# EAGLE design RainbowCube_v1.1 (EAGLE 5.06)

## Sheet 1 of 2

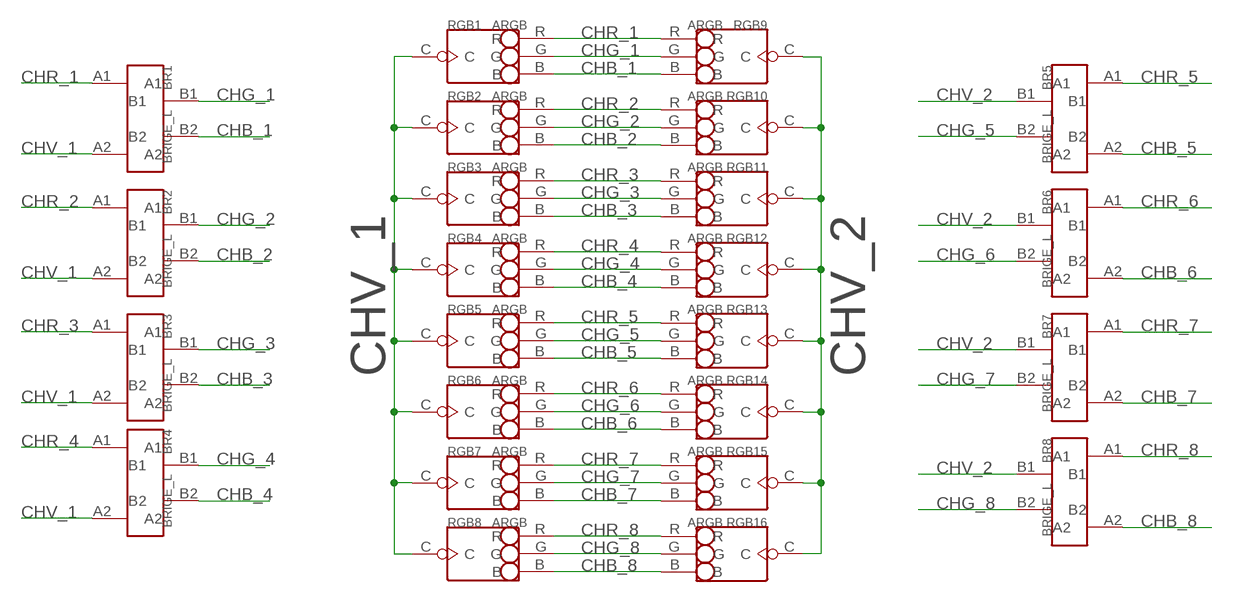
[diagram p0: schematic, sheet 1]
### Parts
BR1  BRIGE_L  [BRIGE_L]
BR2  BRIGE_L  [BRIGE_L]
BR3  BRIGE_L  [BRIGE_L]
BR4  BRIGE_L  [BRIGE_L]
BR5  BRIGE_L  [BRIGE_L]
BR6  BRIGE_L  [BRIGE_L]
BR7  BRIGE_L  [BRIGE_L]
BR8  BRIGE_L  [BRIGE_L]
RGB1  ARGB  [ARGB]
RGB2  ARGB  [ARGB]
RGB3  ARGB  [ARGB]
RGB4  ARGB  [ARGB]
RGB5  ARGB  [ARGB]
RGB6  ARGB  [ARGB]
RGB7  ARGB  [ARGB]
RGB8  ARGB  [ARGB]
RGB9  ARGB  [ARGB]
RGB10  ARGB  [ARGB]
RGB11  ARGB  [ARGB]
RGB12  ARGB  [ARGB]
RGB13  ARGB  [ARGB]
RGB14  ARGB  [ARGB]
RGB15  ARGB  [ARGB]
RGB16  ARGB  [ARGB]

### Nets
CHB_1: BR1.B2 RGB1.B RGB9.B
CHB_2: BR2.B2 RGB2.B RGB10.B
CHB_3: BR3.B2 RGB3.B RGB11.B
CHB_4: BR4.B2 RGB4.B RGB12.B
CHB_5: BR5.A2 RGB5.B RGB13.B
CHB_6: BR6.A2 RGB6.B RGB14.B
CHB_7: BR7.A2 RGB7.B RGB15.B
CHB_8: BR8.A2 RGB8.B RGB16.B
CHG_1: BR1.B1 RGB1.G RGB9.G
CHG_2: BR2.B1 RGB2.G RGB10.G
CHG_3: BR3.B1 RGB3.G RGB11.G
CHG_4: BR4.B1 RGB4.G RGB12.G
CHG_5: BR5.B2 RGB5.G RGB13.G
CHG_6: BR6.B2 RGB6.G RGB14.G
CHG_7: BR7.B2 RGB7.G RGB15.G
CHG_8: BR8.B2 RGB8.G RGB16.G
CHR_1: BR1.A1 RGB1.R RGB9.R
CHR_2: BR2.A1 RGB2.R RGB10.R
CHR_3: BR3.A1 RGB3.R RGB11.R
CHR_4: BR4.A1 RGB4.R RGB12.R
CHR_5: BR5.A1 RGB5.R RGB13.R
CHR_6: BR6.A1 RGB6.R RGB14.R
CHR_7: BR7.A1 RGB7.R RGB15.R
CHR_8: BR8.A1 RGB8.R RGB16.R
CHV_1: BR1.A2 BR2.A2 BR3.A2 BR4.A2 RGB1.C RGB2.C RGB3.C RGB4.C RGB5.C RGB6.C RGB7.C RGB8.C
CHV_2: BR5.B1 BR6.B1 BR7.B1 BR8.B1 RGB9.C RGB10.C RGB11.C RGB12.C RGB13.C RGB14.C RGB15.C RGB16.C

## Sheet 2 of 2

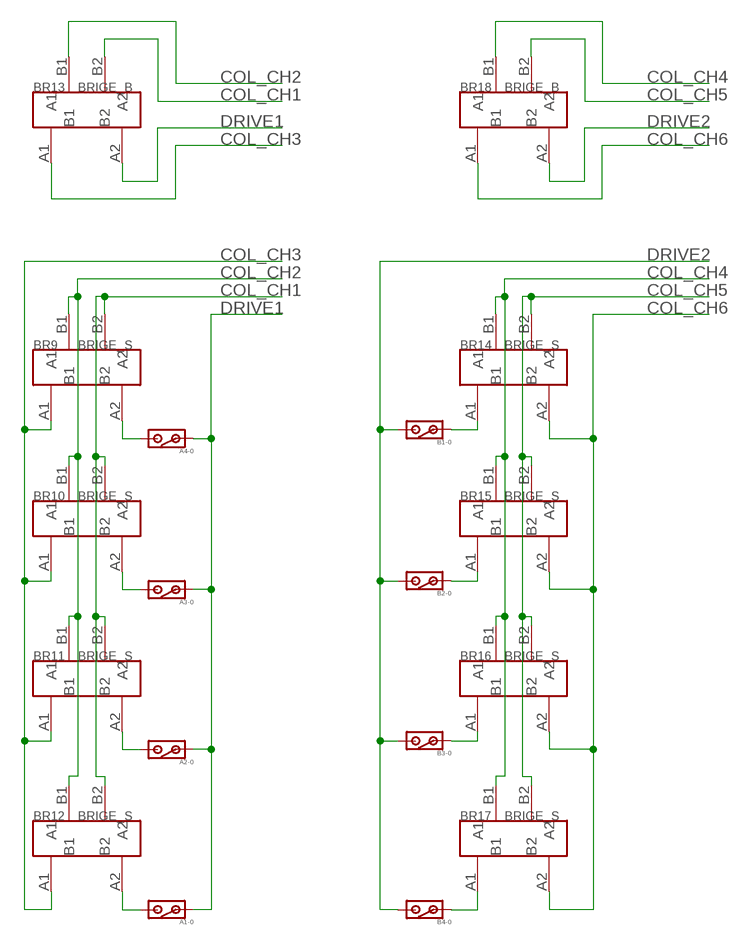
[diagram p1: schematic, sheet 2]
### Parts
A1-0  JP_SW  [JP_SW]
A2-0  JP_SW  [JP_SW]
A3-0  JP_SW  [JP_SW]
A4-0  JP_SW  [JP_SW]
B1-0  JP_SW  [JP_SW]
B2-0  JP_SW  [JP_SW]
B3-0  JP_SW  [JP_SW]
B4-0  JP_SW  [JP_SW]
BR9  BRIGE_S  [BRIGE_S]
BR10  BRIGE_S  [BRIGE_S]
BR11  BRIGE_S  [BRIGE_S]
BR12  BRIGE_S  [BRIGE_S]
BR13  BRIGE_B  [BRIGE_B]
BR14  BRIGE_S  [BRIGE_S]
BR15  BRIGE_S  [BRIGE_S]
BR16  BRIGE_S  [BRIGE_S]
BR17  BRIGE_S  [BRIGE_S]
BR18  BRIGE_B  [BRIGE_B]

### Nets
COL_CH1: BR9.B2 BR10.B2 BR11.B2 BR12.B2 BR13.B2
COL_CH2: BR9.B1 BR10.B1 BR11.B1 BR12.B1 BR13.B1
COL_CH3: BR9.A1 BR10.A1 BR11.A1 BR12.A1 BR13.A1
COL_CH4: BR14.B1 BR15.B1 BR16.B1 BR17.B1 BR18.B1
COL_CH5: BR14.B2 BR15.B2 BR16.B2 BR17.B2 BR18.B2
COL_CH6: BR14.A2 BR15.A2 BR16.A2 BR17.A2 BR18.A1
DRIVE1: A1-0.1 A2-0.1 A3-0.1 A4-0.1 BR13.A2
DRIVE2: B1-0.2 B2-0.2 B3-0.2 B4-0.2 BR18.A2
N$1: B4-0.1 BR17.A1
N$6: B1-0.1 BR14.A1
N$7: B2-0.1 BR15.A1
N$13: B3-0.1 BR16.A1
N$47: A4-0.2 BR9.A2
N$48: A3-0.2 BR10.A2
N$49: A2-0.2 BR11.A2
N$50: A1-0.2 BR12.A2

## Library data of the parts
A1-0 A2-0 A3-0 A4-0 B1-0 B2-0 B3-0 B4-0 = CPT_SMD:JP_SW
BR1-BR18 = CONNECTER:BRIGE
RGB1-RGB16 = CPT_CJ:ARGB

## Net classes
0 default: width 0.003 mm, drill 0.254 mm, clearance 0.152 mm

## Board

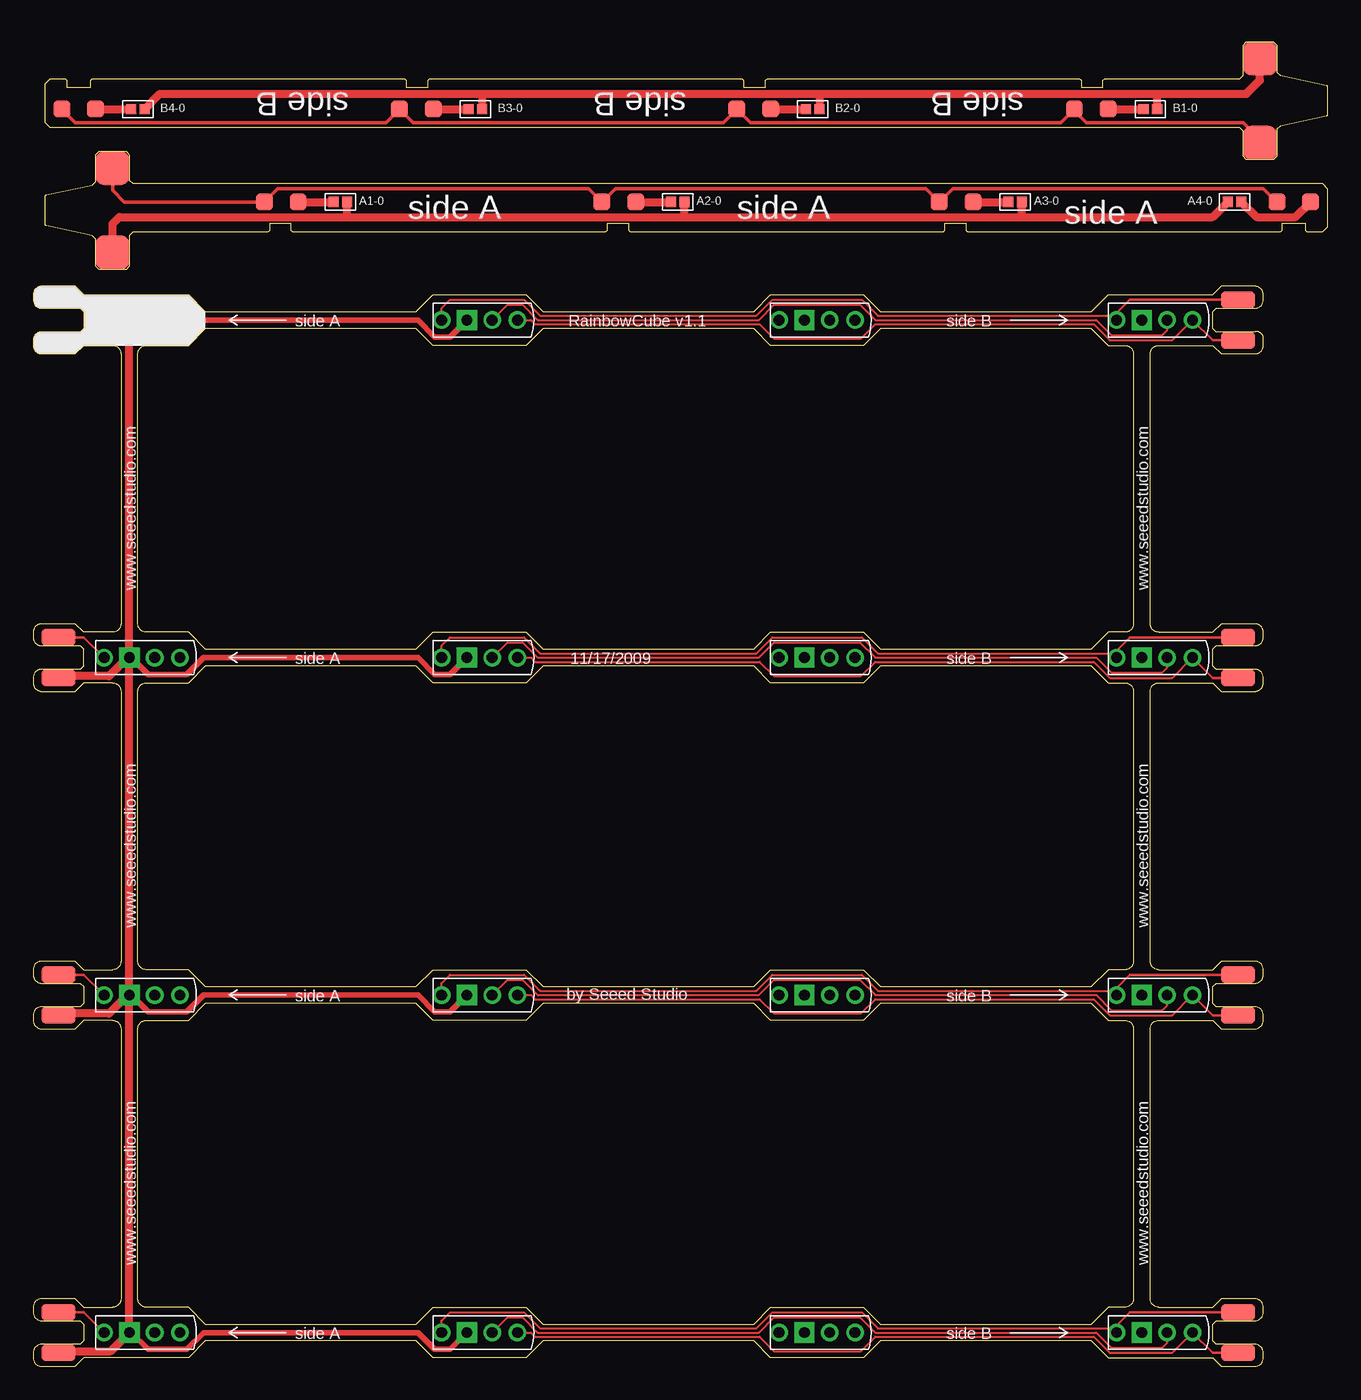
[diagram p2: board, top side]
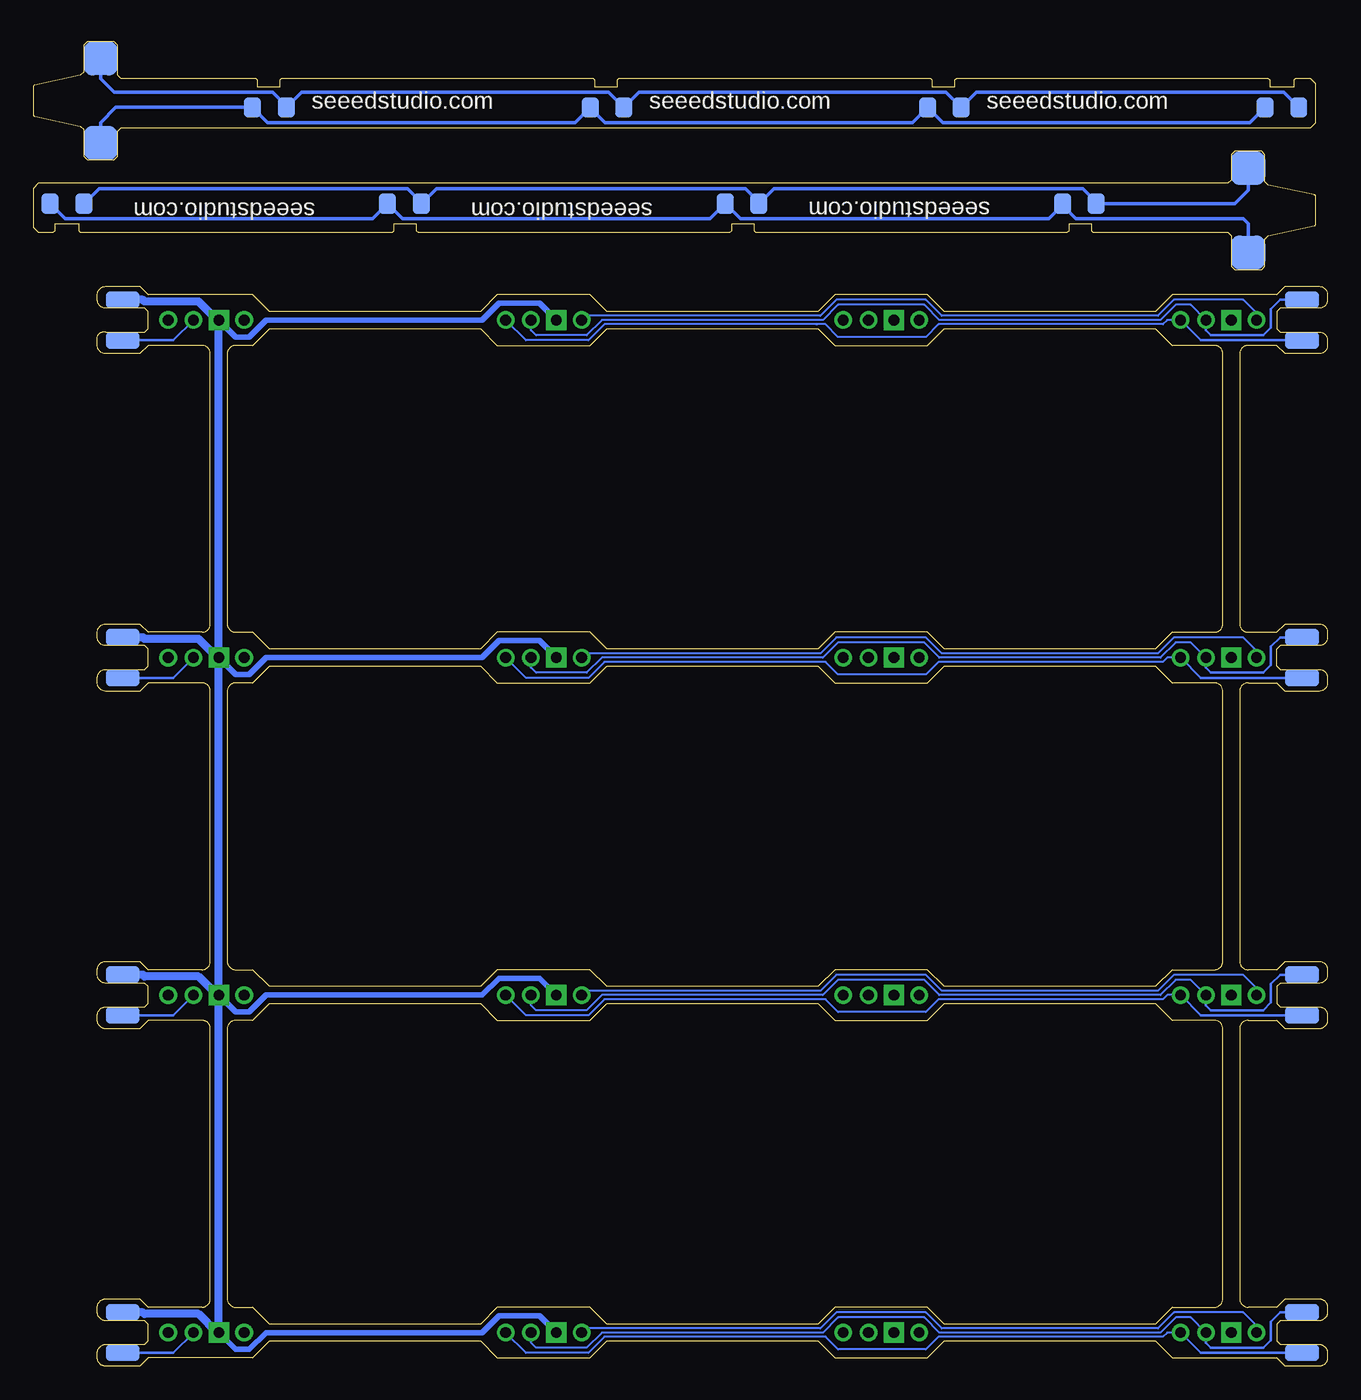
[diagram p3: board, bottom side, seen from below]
Size 97.41 x 99.69 mm. Coordinates in mm from the lower left corner, seen from the top.
Outline: 368 segments
Copper layers (1*16): Top 0.035mm / dielectric 1.5mm / Bottom 0.035mm
Design rules "SeeedStudio_rule_no_angle_090911 *": minimum track width 0.0025mm, minimum drill 10mil, track to track 6mil, track to pad 6mil, pad to pad 6mil, via to via 6mil, smd to smd 0mil, copper to edge 8mil, drill to drill 10mil, minimum pad ring 10mil, minimum via ring 6mil, stop-mask expansion 2mil, vias tented up to drill 100mil, thermal gap 10mil
tRestrict: area 91.9,89.8 to 94.2,90.8; area 91.9,64.4 to 94.2,65.4; area 91.9,39 to 94.2,40; area 91.9,13.6 to 94.2,14.6; area 6.6,13.6 to 8.9,14.6; area 6.6,39 to 8.9,40; area 6.6,64.4 to 8.9,65.4; area 6.6,89.8 to 8.9,90.8

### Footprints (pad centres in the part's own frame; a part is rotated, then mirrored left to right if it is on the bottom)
JP_SW = smd 0.762 x 0.762: 1 0,0.508; 2 0,-0.508
BRIGE_L = smd 2.54 x 1.27: A1 0,1.524; A2 0,-1.524 | smd 2.54 x 1.27 bottom: B1 0,1.524; B2 0,-1.524
BRIGE_S = smd 1.27 x 1.27: A1 -1.27,0; A2 1.27,0 | smd 1.27 x 1.524 bottom: B1 -1.27,-0.127; B2 1.27,-0.127
BRIGE_B = smd 2.54 x 2.54: A1 0,3.175; A2 0,-3.175 | smd 2.54 x 2.54 bottom: B1 0,3.175; B2 0,-3.175
ARGB = drill 0.813 pad 1.321 round: B 3.81,0; G 1.905,0; R -1.905,0 | drill 0.813 pad 1.524 square: C 0,0

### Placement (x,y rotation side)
A1-0  23.11,87.63 270 top
A2-0  48.51,87.63 270 top
A3-0  73.91,87.63 270 top
A4-0  90.42,87.63 90 top
B1-0  84.07,94.61 90 top
B2-0  58.67,94.61 90 top
B3-0  33.27,94.61 90 top
B4-0  7.87,94.61 90 top
BR1  1.91,78.74 0 top
BR2  1.91,53.34 0 top
BR3  1.91,27.94 0 top
BR4  1.91,2.54 0 top
BR5  90.68,78.74 0 top
BR6  90.68,53.34 0 top
BR7  90.68,27.94 0 top
BR8  90.68,2.54 0 top
BR9  94.87,87.63 0 top
BR10  69.47,87.63 0 top
BR11  44.07,87.63 0 top
BR12  18.67,87.63 0 top
BR13  5.97,87 0 top
BR14  79.63,94.61 180 top
BR15  54.23,94.61 180 top
BR16  28.83,94.61 180 top
BR17  3.43,94.61 180 top
BR18  92.33,95.25 180 top
RGB1  7.24,78.74 0 top
RGB2  7.24,53.34 0 top
RGB3  7.24,27.94 0 top
RGB4  7.24,2.54 0 top
RGB5  32.64,78.74 0 top
RGB6  32.64,53.34 0 top
RGB7  32.64,27.94 0 top
RGB8  32.64,2.54 0 top
RGB9  58.04,78.74 0 top
RGB10  58.04,53.34 0 top
RGB11  58.04,27.94 0 top
RGB12  58.04,2.54 0 top
RGB13  83.44,78.74 0 top
RGB14  83.44,53.34 0 top
RGB15  83.44,27.94 0 top
RGB16  83.44,2.54 0 top

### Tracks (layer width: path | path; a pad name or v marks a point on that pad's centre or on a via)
CHB_1
  Bottom 0.152: RGB1.B 12.06,78.74 12.38,78.42 29.27,78.42 30.23,77.47 36.83,77.47 37.78,78.42 38.42,78.42 | 38.42,78.42 38.48,78.42 | 38.42,78.42 54.42,78.42 55.63,77.22 60.33,77.22 RGB9.B
  Bottom 0.203: RGB1.B 9.53,77.22 BR1.B2
CHB_2
  Bottom 0.152: RGB2.B 12.06,53.34 12.38,53.02 29.27,53.02 30.23,52.07 36.83,52.07 37.78,53.02 38.42,53.02 | 38.42,53.02 38.48,53.02 | 38.42,53.02 54.42,53.02 55.63,51.82 60.33,51.82 RGB10.B
  Bottom 0.203: RGB2.B 9.53,51.82 BR2.B2
CHB_3
  Bottom 0.152: RGB3.B 12.06,27.94 12.38,27.62 29.27,27.62 30.23,26.67 36.83,26.67 37.78,27.62 38.42,27.62 | 38.42,27.62 38.48,27.62 | 38.42,27.62 54.42,27.62 55.63,26.42 60.33,26.42 RGB11.B
  Bottom 0.203: RGB3.B 9.53,26.42 BR3.B2
CHB_4
  Bottom 0.152: RGB4.B 12.06,2.54 12.38,2.22 29.27,2.22 30.23,1.27 36.83,1.27 37.78,2.22 38.42,2.22 | 38.42,2.22 38.48,2.22 | 38.42,2.22 54.42,2.22 55.63,1.02 60.33,1.02 RGB12.B
  Bottom 0.203: RGB4.B 9.53,1.02 BR4.B2
CHB_5
  Top 0.152: RGB5.B 37.46,78.74 37.78,78.42 54.67,78.42 55.75,77.34 62.29,77.34 63.37,78.42 79.82,78.42 81.03,77.22 85.72,77.22 RGB13.B
  Top 0.203: RGB13.B 88.77,77.22 BR5.A2
CHB_6
  Top 0.152: RGB6.B 37.46,53.34 37.78,53.02 54.67,53.02 55.75,51.94 62.29,51.94 63.37,53.02 79.82,53.02 81.03,51.82 85.72,51.82 RGB14.B
  Top 0.203: RGB14.B 88.77,51.82 BR6.A2
CHB_7
  Top 0.152: RGB7.B 37.46,27.94 37.78,27.62 54.67,27.62 55.75,26.54 62.29,26.54 63.37,27.62 79.82,27.62 81.03,26.42 85.72,26.42 RGB15.B
  Top 0.203: RGB15.B 88.77,26.42 BR7.A2
CHB_8
  Top 0.152: RGB8.B 37.46,2.54 37.78,2.22 54.67,2.22 55.75,1.14 62.29,1.14 63.37,2.22 79.82,2.22 81.03,1.02 85.72,1.02 RGB16.B
  Top 0.203: RGB16.B 88.77,1.02 BR8.A2
CHG_1
  Bottom 0.152: RGB1.G 10.29,79.88 11.43,79.88 12.57,78.74 29.21,78.74 30.35,79.88 36.83,79.88 37.97,78.74 54.61,78.74 55.75,77.6 59.56,77.6 59.94,77.98 RGB9.G
  Bottom 0.203: RGB1.G 9.14,77.98 8.76,77.6 4.83,77.6 4.25,78.17 4.25,79.57 3.56,80.26 BR1.B1
CHG_2
  Bottom 0.152: RGB2.G 10.29,54.48 11.43,54.48 12.57,53.34 29.21,53.34 30.35,54.48 36.83,54.48 37.97,53.34 54.61,53.34 55.75,52.2 59.56,52.2 59.94,52.58 RGB10.G
  Bottom 0.203: RGB2.G 9.14,52.58 8.76,52.2 4.83,52.2 4.25,52.77 4.25,54.17 3.56,54.86 BR2.B1
CHG_3
  Bottom 0.152: RGB3.G 10.29,29.08 11.43,29.08 12.57,27.94 29.21,27.94 30.35,29.08 36.83,29.08 37.97,27.94 54.61,27.94 55.75,26.8 59.56,26.8 59.94,27.18 RGB11.G
  Bottom 0.203: RGB3.G 9.14,27.18 8.76,26.8 4.83,26.8 4.25,27.37 4.25,28.77 3.56,29.46 BR3.B1
CHG_4
  Bottom 0.152: RGB4.G 10.29,3.68 11.43,3.68 12.57,2.54 29.21,2.54 30.35,3.68 36.83,3.68 37.97,2.54 54.61,2.54 55.75,1.4 59.56,1.4 59.94,1.78 RGB12.G
  Bottom 0.203: RGB4.G 9.14,1.78 8.76,1.4 4.83,1.4 4.25,1.97 4.25,3.37 3.56,4.06 BR4.B1
CHG_5
  Top 0.152: RGB5.G 35.69,79.88 36.83,79.88 37.97,78.74 54.61,78.74 55.75,79.88 62.23,79.88 63.37,78.74 80.01,78.74 81.15,77.6 84.96,77.6 85.34,77.98 RGB13.G
  Bottom 0.203: BR5.B2 86.87,77.22 RGB13.G
CHG_6
  Top 0.152: RGB6.G 35.69,54.48 36.83,54.48 37.97,53.34 54.61,53.34 55.75,54.48 62.23,54.48 63.37,53.34 80.01,53.34 81.15,52.2 84.96,52.2 85.34,52.58 RGB14.G
  Bottom 0.203: BR6.B2 86.87,51.82 RGB14.G
CHG_7
  Top 0.152: RGB7.G 35.69,29.08 36.83,29.08 37.97,27.94 54.61,27.94 55.75,29.08 62.23,29.08 63.37,27.94 80.01,27.94 81.15,26.8 84.96,26.8 85.34,27.18 RGB15.G
  Bottom 0.203: BR7.B2 86.87,26.42 RGB15.G
CHG_8
  Top 0.152: RGB8.G 35.69,3.68 36.83,3.68 37.97,2.54 54.61,2.54 55.75,3.68 62.23,3.68 63.37,2.54 80.01,2.54 81.15,1.4 84.96,1.4 85.34,1.78 RGB16.G
  Bottom 0.203: BR8.B2 86.87,1.02 RGB16.G
CHR_1
  Top 0.203: BR1.A1 3.81,80.26 RGB1.R
  Bottom 0.152: RGB1.R 5.33,79.25 6.35,80.26 11.56,80.26 12.76,79.06 29.02,79.06 30.23,80.26 36.96,80.26 38.16,79.06 55.82,79.06 RGB9.R
CHR_2
  Top 0.203: BR2.A1 3.81,54.86 RGB2.R
  Bottom 0.152: RGB2.R 5.33,53.85 6.35,54.86 11.56,54.86 12.76,53.66 29.02,53.66 30.23,54.86 36.96,54.86 38.16,53.66 55.82,53.66 RGB10.R
CHR_3
  Top 0.203: BR3.A1 3.81,29.46 RGB3.R
  Bottom 0.152: RGB3.R 5.33,28.45 6.35,29.46 11.56,29.46 12.76,28.26 29.02,28.26 30.23,29.46 36.96,29.46 38.16,28.26 55.82,28.26 RGB11.R
CHR_4
  Top 0.203: BR4.A1 3.81,4.06 RGB4.R
  Bottom 0.152: RGB4.R 5.33,3.05 6.35,4.06 11.56,4.06 12.76,2.86 29.02,2.86 30.23,4.06 36.96,4.06 38.16,2.86 55.82,2.86 RGB12.R
CHR_5
  Top 0.152: RGB5.R 30.73,79.63 31.37,80.26 36.96,80.26 38.16,79.06 54.42,79.06 55.63,80.26 62.36,80.26 63.56,79.06 81.22,79.06 RGB13.R
  Top 0.203: BR5.A1 82.55,80.26 81.53,79.25 RGB13.R
CHR_6
  Top 0.152: RGB6.R 30.73,54.23 31.37,54.86 36.96,54.86 38.16,53.66 54.42,53.66 55.63,54.86 62.36,54.86 63.56,53.66 81.22,53.66 RGB14.R
  Top 0.203: BR6.A1 82.55,54.86 81.53,53.85 RGB14.R
CHR_7
  Top 0.152: RGB7.R 30.73,28.83 31.37,29.46 36.96,29.46 38.16,28.26 54.42,28.26 55.63,29.46 62.36,29.46 63.56,28.26 81.22,28.26 RGB15.R
  Top 0.203: BR7.A1 82.55,29.46 81.53,28.45 RGB15.R
CHR_8
  Top 0.152: RGB8.R 30.73,3.43 31.37,4.06 36.96,4.06 38.16,2.86 54.42,2.86 55.63,4.06 62.36,4.06 63.56,2.86 81.22,2.86 RGB16.R
  Top 0.203: BR8.A1 82.55,4.06 81.53,3.05 RGB16.R
CHV_1
  Top 0.406: RGB1.C 7.37,78.74 8.64,77.47 11.56,77.47 12.83,78.74 28.96,78.74 30.23,77.47 31.37,77.47 RGB5.C | RGB2.C 7.37,53.34 8.64,52.07 11.56,52.07 12.83,53.34 28.96,53.34 30.23,52.07 31.37,52.07 RGB6.C | RGB3.C 7.37,27.94 8.64,26.67 11.56,26.67 12.83,27.94 28.96,27.94 30.23,26.67 31.37,26.67 RGB7.C | RGB4.C 7.37,2.54 8.64,1.27 11.56,1.27 12.83,2.54 28.96,2.54 30.23,1.27 31.37,1.27 RGB8.C
  Top 0.61: BR1.A2 2.03,77.34 5.71,77.34 7.11,78.74 RGB1.C RGB2.C | BR2.A2 2.03,51.94 5.71,51.94 7.11,53.34 RGB2.C | BR3.A2 2.03,26.54 5.71,26.54 7.11,27.94 RGB3.C | BR4.A2 2.03,1.14 5.84,1.14 RGB4.C RGB3.C | RGB3.C RGB2.C
CHV_2
  Bottom 0.406: RGB9.C 59.31,80.01 62.36,80.01 63.63,78.74 79.88,78.74 81.15,77.47 82.17,77.47 RGB13.C | RGB10.C 59.31,54.61 62.36,54.61 63.63,53.34 79.88,53.34 81.15,52.07 82.17,52.07 RGB14.C | RGB11.C 59.31,29.21 62.36,29.21 63.63,27.94 79.88,27.94 81.15,26.67 82.17,26.67 RGB15.C | RGB12.C 59.31,3.81 62.36,3.81 63.63,2.54 79.88,2.54 81.15,1.27 82.17,1.27 RGB16.C
  Bottom 0.61: BR5.B1 89.15,80.26 89.03,80.14 84.96,80.14 83.57,78.74 RGB13.C RGB14.C | BR6.B1 89.15,54.86 89.03,54.74 84.96,54.74 83.57,53.34 RGB14.C | BR7.B1 89.15,29.46 89.03,29.34 84.96,29.34 83.57,27.94 RGB15.C | BR8.B1 89.15,4.06 89.03,3.94 84.96,3.94 83.57,2.54 RGB16.C RGB15.C | RGB15.C RGB14.C
COL_CH1
  Bottom 0.254: 19.94,87.38 BR12.B2 | 19.94,87.38 18.92,86.36 6.35,86.36 5.97,85.98 BR13.B2 | 19.94,87.38 20.95,86.36 44.2,86.36 BR11.B2 46.48,86.36 69.6,86.36 BR10.B2 71.88,86.36 95,86.36 BR9.B2
COL_CH2
  Bottom 0.254: BR13.B1 5.97,88.52 6.98,87.5 BR12.B1 17.4,87.63 18.41,88.65 41.66,88.65 BR11.B1 42.8,87.63 43.81,88.65 67.06,88.65 BR10.B1 68.2,87.63 69.22,88.65 92.46,88.65 BR9.B1
COL_CH3
  Top 0.254: BR13.A1 5.97,88.52 6.86,87.63 BR12.A1 18.41,88.65 41.78,88.65 BR11.A1 43.81,88.65 67.18,88.65 BR10.A1 69.22,88.65 92.58,88.65 BR9.A1
COL_CH4
  Bottom 0.254: BR17.B1 5.84,93.6 28.96,93.6 BR16.B1 31.24,93.6 54.36,93.6 BR15.B1 56.64,93.6 79.76,93.6 BR14.B1 91.19,94.74 92.33,93.6 BR18.B1
COL_CH5
  Bottom 0.254: BR17.B2 3.3,95.89 26.42,95.89 BR16.B2 28.7,95.89 51.82,95.89 BR15.B2 54.1,95.89 77.22,95.89 BR14.B2 78.36,94.87 79.38,95.89 91.31,95.89 92.33,96.9 BR18.B2
COL_CH6
  Top 0.254: BR17.A2 3.17,93.6 26.54,93.6 BR16.A2 28.57,93.6 51.94,93.6 BR15.A2 53.98,93.6 77.34,93.6 BR14.A2 78.36,94.49 79.25,93.6 91.06,93.6 92.33,92.33 BR18.A1
DRIVE1
  Top 0.61: A4-0.1 88.77,86.49 74.42,86.49 | 49.02,86.49 74.42,86.49 | 49.02,86.49 A2-0.1 | 74.42,86.49 A3-0.1 | 23.62,86.49 49.02,86.49 | 23.62,86.49 A1-0.1 | 23.62,86.49 6.48,86.49 5.97,85.98 BR13.A2
DRIVE2
  Top 0.61: 33.78,95.76 59.18,95.76 | 33.78,95.76 9.53,95.76 B4-0.2 | 59.18,95.76 B2-0.2 | 33.78,95.76 B3-0.2 | 59.18,95.76 84.58,95.76 | 84.58,95.76 91.31,95.76 92.33,96.77 BR18.A2 | 84.58,95.76 B1-0.2
N$1
  Top 0.61: BR17.A1 B4-0.1
N$6
  Top 0.61: BR14.A1 B1-0.1
N$7
  Top 0.61: BR15.A1 B2-0.1
N$13
  Top 0.61: BR16.A1 B3-0.1
N$47
  Top 0.61: BR9.A2 95,86.49 92.08,86.49 A4-0.2
N$48
  Top 0.61: BR10.A2 A3-0.2
N$49
  Top 0.61: BR11.A2 A2-0.2
N$50
  Top 0.61: BR12.A2 A1-0.2

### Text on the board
tPlace: side B | side B | side B | side A | side A | side A | side A | RainbowCube v1.1 | side B | www.seeedstudio.com | www.seeedstudio.com | side A | 11/17/2009 | side B | www.seeedstudio.com | www.seeedstudio.com | by Seeed Studio | side A | side B | www.seeedstudio.com | www.seeedstudio.com | side A | side B
bPlace: seeedstudio.com | seeedstudio.com | seeedstudio.com | seeedstudio.com | seeedstudio.com | seeedstudio.com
